VERSION 5.7 ;
  NOWIREEXTENSIONATPIN ON ;
  DIVIDERCHAR "/" ;
  BUSBITCHARS "[]" ;
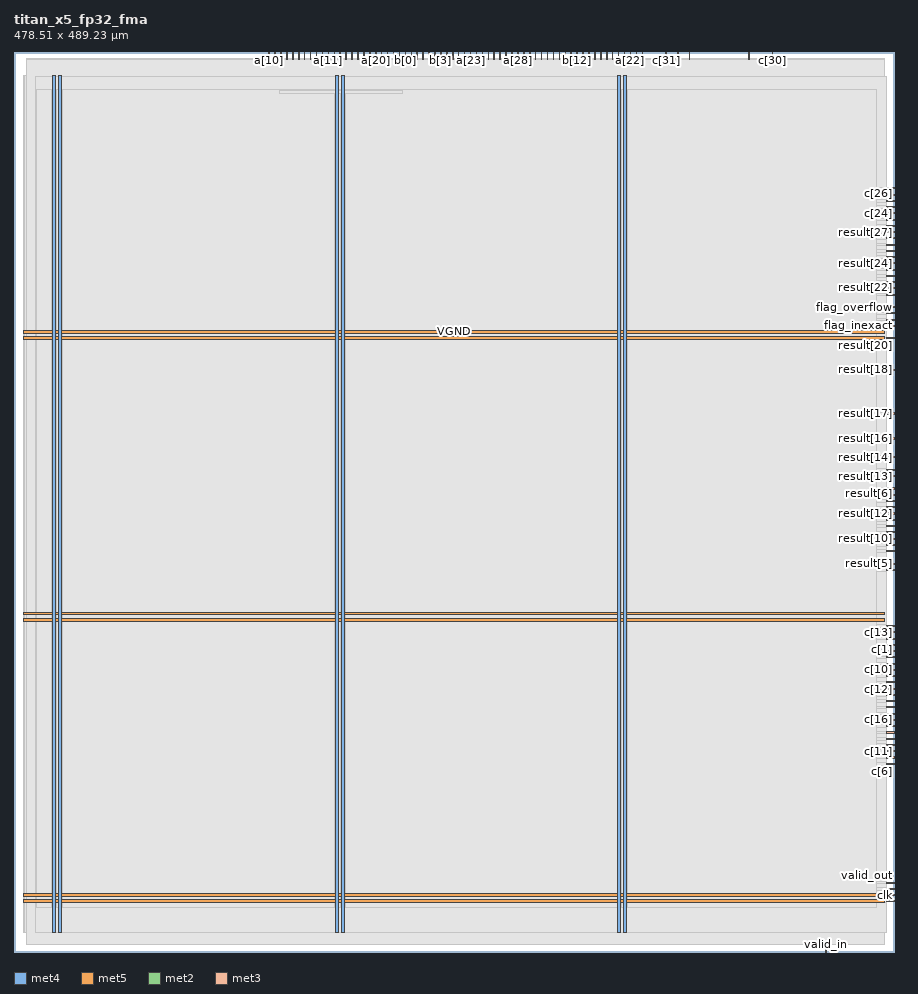
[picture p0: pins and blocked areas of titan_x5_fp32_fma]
MACRO titan_x5_fp32_fma
  CLASS BLOCK ;
  FOREIGN titan_x5_fp32_fma ;
  ORIGIN 0.000 0.000 ;
  SIZE 478.510 BY 489.230 ;
  PIN VGND
    DIRECTION INOUT ;
    USE GROUND ;
    PORT
      LAYER met4 ;
        RECT 24.340 10.640 25.940 476.240 ;
    END
    PORT
      LAYER met4 ;
        RECT 177.940 10.640 179.540 476.240 ;
    END
    PORT
      LAYER met4 ;
        RECT 331.540 10.640 333.140 476.240 ;
    END
    PORT
      LAYER met5 ;
        RECT 5.280 30.030 473.120 31.630 ;
    END
    PORT
      LAYER met5 ;
        RECT 5.280 183.210 473.120 184.810 ;
    END
    PORT
      LAYER met5 ;
        RECT 5.280 336.390 473.120 337.990 ;
    END
  END VGND
  PIN VPWR
    DIRECTION INOUT ;
    USE POWER ;
    PORT
      LAYER met4 ;
        RECT 21.040 10.640 22.640 476.240 ;
    END
    PORT
      LAYER met4 ;
        RECT 174.640 10.640 176.240 476.240 ;
    END
    PORT
      LAYER met4 ;
        RECT 328.240 10.640 329.840 476.240 ;
    END
    PORT
      LAYER met5 ;
        RECT 5.280 26.730 473.120 28.330 ;
    END
    PORT
      LAYER met5 ;
        RECT 5.280 179.910 473.120 181.510 ;
    END
    PORT
      LAYER met5 ;
        RECT 5.280 333.090 473.120 334.690 ;
    END
  END VPWR
  PIN a[0]
    DIRECTION INPUT ;
    USE SIGNAL ;
    ANTENNAGATEAREA 0.196500 ;
    PORT
      LAYER met2 ;
        RECT 199.730 485.230 200.010 489.230 ;
    END
  END a[0]
  PIN a[10]
    DIRECTION INPUT ;
    USE SIGNAL ;
    ANTENNAGATEAREA 0.196500 ;
    PORT
      LAYER met2 ;
        RECT 138.550 485.230 138.830 489.230 ;
    END
  END a[10]
  PIN a[11]
    DIRECTION INPUT ;
    USE SIGNAL ;
    ANTENNAGATEAREA 0.196500 ;
    PORT
      LAYER met2 ;
        RECT 170.750 485.230 171.030 489.230 ;
    END
  END a[11]
  PIN a[12]
    DIRECTION INPUT ;
    USE SIGNAL ;
    ANTENNAGATEAREA 0.196500 ;
    PORT
      LAYER met2 ;
        RECT 157.870 485.230 158.150 489.230 ;
    END
  END a[12]
  PIN a[13]
    DIRECTION INPUT ;
    USE SIGNAL ;
    ANTENNAGATEAREA 0.196500 ;
    PORT
      LAYER met2 ;
        RECT 173.970 485.230 174.250 489.230 ;
    END
  END a[13]
  PIN a[14]
    DIRECTION INPUT ;
    USE SIGNAL ;
    ANTENNAGATEAREA 0.196500 ;
    PORT
      LAYER met2 ;
        RECT 177.190 485.230 177.470 489.230 ;
    END
  END a[14]
  PIN a[15]
    DIRECTION INPUT ;
    USE SIGNAL ;
    ANTENNAGATEAREA 0.196500 ;
    PORT
      LAYER met2 ;
        RECT 141.770 485.230 142.050 489.230 ;
    END
  END a[15]
  PIN a[16]
    DIRECTION INPUT ;
    USE SIGNAL ;
    ANTENNAGATEAREA 0.196500 ;
    PORT
      LAYER met2 ;
        RECT 154.650 485.230 154.930 489.230 ;
    END
  END a[16]
  PIN a[17]
    DIRECTION INPUT ;
    USE SIGNAL ;
    ANTENNAGATEAREA 0.196500 ;
    PORT
      LAYER met2 ;
        RECT 164.310 485.230 164.590 489.230 ;
    END
  END a[17]
  PIN a[18]
    DIRECTION INPUT ;
    USE SIGNAL ;
    ANTENNAGATEAREA 0.196500 ;
    PORT
      LAYER met2 ;
        RECT 180.410 485.230 180.690 489.230 ;
    END
  END a[18]
  PIN a[19]
    DIRECTION INPUT ;
    USE SIGNAL ;
    ANTENNAGATEAREA 0.196500 ;
    PORT
      LAYER met2 ;
        RECT 148.210 485.230 148.490 489.230 ;
    END
  END a[19]
  PIN a[1]
    DIRECTION INPUT ;
    USE SIGNAL ;
    ANTENNAGATEAREA 0.126000 ;
    PORT
      LAYER met2 ;
        RECT 206.170 485.230 206.450 489.230 ;
    END
  END a[1]
  PIN a[20]
    DIRECTION INPUT ;
    USE SIGNAL ;
    ANTENNAGATEAREA 0.196500 ;
    PORT
      LAYER met2 ;
        RECT 196.510 485.230 196.790 489.230 ;
    END
  END a[20]
  PIN a[21]
    DIRECTION INPUT ;
    USE SIGNAL ;
    ANTENNAGATEAREA 0.196500 ;
    PORT
      LAYER met2 ;
        RECT 202.950 485.230 203.230 489.230 ;
    END
  END a[21]
  PIN a[22]
    DIRECTION INPUT ;
    USE SIGNAL ;
    ANTENNAGATEAREA 0.213000 ;
    PORT
      LAYER met2 ;
        RECT 334.970 485.230 335.250 489.230 ;
    END
  END a[22]
  PIN a[23]
    DIRECTION INPUT ;
    USE SIGNAL ;
    ANTENNAGATEAREA 0.196500 ;
    PORT
      LAYER met2 ;
        RECT 248.030 485.230 248.310 489.230 ;
    END
  END a[23]
  PIN a[24]
    DIRECTION INPUT ;
    USE SIGNAL ;
    ANTENNAGATEAREA 0.196500 ;
    PORT
      LAYER met2 ;
        RECT 251.250 485.230 251.530 489.230 ;
    END
  END a[24]
  PIN a[25]
    DIRECTION INPUT ;
    USE SIGNAL ;
    ANTENNAGATEAREA 0.196500 ;
    PORT
      LAYER met2 ;
        RECT 209.390 485.230 209.670 489.230 ;
    END
  END a[25]
  PIN a[26]
    DIRECTION INPUT ;
    USE SIGNAL ;
    ANTENNAGATEAREA 0.196500 ;
    PORT
      LAYER met2 ;
        RECT 244.810 485.230 245.090 489.230 ;
    END
  END a[26]
  PIN a[27]
    DIRECTION INPUT ;
    USE SIGNAL ;
    ANTENNAGATEAREA 0.196500 ;
    PORT
      LAYER met2 ;
        RECT 289.890 485.230 290.170 489.230 ;
    END
  END a[27]
  PIN a[28]
    DIRECTION INPUT ;
    USE SIGNAL ;
    ANTENNAGATEAREA 0.196500 ;
    PORT
      LAYER met2 ;
        RECT 273.790 485.230 274.070 489.230 ;
    END
  END a[28]
  PIN a[29]
    DIRECTION INPUT ;
    USE SIGNAL ;
    ANTENNAGATEAREA 0.196500 ;
    PORT
      LAYER met2 ;
        RECT 286.670 485.230 286.950 489.230 ;
    END
  END a[29]
  PIN a[2]
    DIRECTION INPUT ;
    USE SIGNAL ;
    ANTENNAGATEAREA 0.196500 ;
    PORT
      LAYER met2 ;
        RECT 190.070 485.230 190.350 489.230 ;
    END
  END a[2]
  PIN a[30]
    DIRECTION INPUT ;
    USE SIGNAL ;
    ANTENNAGATEAREA 0.196500 ;
    PORT
      LAYER met2 ;
        RECT 277.010 485.230 277.290 489.230 ;
    END
  END a[30]
  PIN a[31]
    DIRECTION INPUT ;
    USE SIGNAL ;
    ANTENNAGATEAREA 0.196500 ;
    PORT
      LAYER met2 ;
        RECT 341.410 485.230 341.690 489.230 ;
    END
  END a[31]
  PIN a[3]
    DIRECTION INPUT ;
    USE SIGNAL ;
    ANTENNAGATEAREA 0.196500 ;
    PORT
      LAYER met2 ;
        RECT 193.290 485.230 193.570 489.230 ;
    END
  END a[3]
  PIN a[4]
    DIRECTION INPUT ;
    USE SIGNAL ;
    ANTENNAGATEAREA 0.196500 ;
    PORT
      LAYER met2 ;
        RECT 167.530 485.230 167.810 489.230 ;
    END
  END a[4]
  PIN a[5]
    DIRECTION INPUT ;
    USE SIGNAL ;
    ANTENNAGATEAREA 0.196500 ;
    PORT
      LAYER met2 ;
        RECT 186.850 485.230 187.130 489.230 ;
    END
  END a[5]
  PIN a[6]
    DIRECTION INPUT ;
    USE SIGNAL ;
    ANTENNAGATEAREA 0.126000 ;
    PORT
      LAYER met2 ;
        RECT 144.990 485.230 145.270 489.230 ;
    END
  END a[6]
  PIN a[7]
    DIRECTION INPUT ;
    USE SIGNAL ;
    ANTENNAGATEAREA 0.126000 ;
    PORT
      LAYER met2 ;
        RECT 183.630 485.230 183.910 489.230 ;
    END
  END a[7]
  PIN a[8]
    DIRECTION INPUT ;
    USE SIGNAL ;
    ANTENNAGATEAREA 0.196500 ;
    PORT
      LAYER met2 ;
        RECT 151.430 485.230 151.710 489.230 ;
    END
  END a[8]
  PIN a[9]
    DIRECTION INPUT ;
    USE SIGNAL ;
    ANTENNAGATEAREA 0.196500 ;
    PORT
      LAYER met2 ;
        RECT 161.090 485.230 161.370 489.230 ;
    END
  END a[9]
  PIN b[0]
    DIRECTION INPUT ;
    USE SIGNAL ;
    ANTENNAGATEAREA 0.126000 ;
    PORT
      LAYER met2 ;
        RECT 212.610 485.230 212.890 489.230 ;
    END
  END b[0]
  PIN b[10]
    DIRECTION INPUT ;
    USE SIGNAL ;
    ANTENNAGATEAREA 0.126000 ;
    PORT
      LAYER met2 ;
        RECT 322.090 485.230 322.370 489.230 ;
    END
  END b[10]
  PIN b[11]
    DIRECTION INPUT ;
    USE SIGNAL ;
    ANTENNAGATEAREA 0.126000 ;
    PORT
      LAYER met2 ;
        RECT 302.770 485.230 303.050 489.230 ;
    END
  END b[11]
  PIN b[12]
    DIRECTION INPUT ;
    USE SIGNAL ;
    ANTENNAGATEAREA 0.126000 ;
    PORT
      LAYER met2 ;
        RECT 305.990 485.230 306.270 489.230 ;
    END
  END b[12]
  PIN b[13]
    DIRECTION INPUT ;
    USE SIGNAL ;
    ANTENNAGATEAREA 0.196500 ;
    PORT
      LAYER met2 ;
        RECT 264.130 485.230 264.410 489.230 ;
    END
  END b[13]
  PIN b[14]
    DIRECTION INPUT ;
    USE SIGNAL ;
    ANTENNAGATEAREA 0.126000 ;
    PORT
      LAYER met2 ;
        RECT 312.430 485.230 312.710 489.230 ;
    END
  END b[14]
  PIN b[15]
    DIRECTION INPUT ;
    USE SIGNAL ;
    ANTENNAGATEAREA 0.196500 ;
    PORT
      LAYER met2 ;
        RECT 260.910 485.230 261.190 489.230 ;
    END
  END b[15]
  PIN b[16]
    DIRECTION INPUT ;
    USE SIGNAL ;
    ANTENNAGATEAREA 0.196500 ;
    PORT
      LAYER met2 ;
        RECT 267.350 485.230 267.630 489.230 ;
    END
  END b[16]
  PIN b[17]
    DIRECTION INPUT ;
    USE SIGNAL ;
    ANTENNAGATEAREA 0.196500 ;
    PORT
      LAYER met2 ;
        RECT 270.570 485.230 270.850 489.230 ;
    END
  END b[17]
  PIN b[18]
    DIRECTION INPUT ;
    USE SIGNAL ;
    ANTENNAGATEAREA 0.196500 ;
    PORT
      LAYER met2 ;
        RECT 257.690 485.230 257.970 489.230 ;
    END
  END b[18]
  PIN b[19]
    DIRECTION INPUT ;
    USE SIGNAL ;
    ANTENNAGATEAREA 0.126000 ;
    PORT
      LAYER met2 ;
        RECT 318.870 485.230 319.150 489.230 ;
    END
  END b[19]
  PIN b[1]
    DIRECTION INPUT ;
    USE SIGNAL ;
    ANTENNAGATEAREA 0.196500 ;
    PORT
      LAYER met2 ;
        RECT 222.270 485.230 222.550 489.230 ;
    END
  END b[1]
  PIN b[20]
    DIRECTION INPUT ;
    USE SIGNAL ;
    ANTENNAGATEAREA 0.196500 ;
    PORT
      LAYER met2 ;
        RECT 331.750 485.230 332.030 489.230 ;
    END
  END b[20]
  PIN b[21]
    DIRECTION INPUT ;
    USE SIGNAL ;
    ANTENNAGATEAREA 0.196500 ;
    PORT
      LAYER met2 ;
        RECT 254.470 485.230 254.750 489.230 ;
    END
  END b[21]
  PIN b[22]
    DIRECTION INPUT ;
    USE SIGNAL ;
    ANTENNAGATEAREA 0.213000 ;
    PORT
      LAYER met2 ;
        RECT 293.110 485.230 293.390 489.230 ;
    END
  END b[22]
  PIN b[23]
    DIRECTION INPUT ;
    USE SIGNAL ;
    ANTENNAGATEAREA 0.196500 ;
    PORT
      LAYER met2 ;
        RECT 328.530 485.230 328.810 489.230 ;
    END
  END b[23]
  PIN b[24]
    DIRECTION INPUT ;
    USE SIGNAL ;
    ANTENNAGATEAREA 0.126000 ;
    PORT
      LAYER met2 ;
        RECT 325.310 485.230 325.590 489.230 ;
    END
  END b[24]
  PIN b[25]
    DIRECTION INPUT ;
    USE SIGNAL ;
    ANTENNAGATEAREA 0.126000 ;
    PORT
      LAYER met2 ;
        RECT 315.650 485.230 315.930 489.230 ;
    END
  END b[25]
  PIN b[26]
    DIRECTION INPUT ;
    USE SIGNAL ;
    ANTENNAGATEAREA 0.196500 ;
    PORT
      LAYER met2 ;
        RECT 309.210 485.230 309.490 489.230 ;
    END
  END b[26]
  PIN b[27]
    DIRECTION INPUT ;
    USE SIGNAL ;
    ANTENNAGATEAREA 0.196500 ;
    PORT
      LAYER met2 ;
        RECT 299.550 485.230 299.830 489.230 ;
    END
  END b[27]
  PIN b[28]
    DIRECTION INPUT ;
    USE SIGNAL ;
    ANTENNAGATEAREA 0.196500 ;
    PORT
      LAYER met2 ;
        RECT 296.330 485.230 296.610 489.230 ;
    END
  END b[28]
  PIN b[29]
    DIRECTION INPUT ;
    USE SIGNAL ;
    ANTENNAGATEAREA 0.196500 ;
    PORT
      LAYER met2 ;
        RECT 280.230 485.230 280.510 489.230 ;
    END
  END b[29]
  PIN b[2]
    DIRECTION INPUT ;
    USE SIGNAL ;
    ANTENNAGATEAREA 0.196500 ;
    PORT
      LAYER met2 ;
        RECT 225.490 485.230 225.770 489.230 ;
    END
  END b[2]
  PIN b[30]
    DIRECTION INPUT ;
    USE SIGNAL ;
    ANTENNAGATEAREA 0.196500 ;
    PORT
      LAYER met2 ;
        RECT 283.450 485.230 283.730 489.230 ;
    END
  END b[30]
  PIN b[31]
    DIRECTION INPUT ;
    USE SIGNAL ;
    ANTENNAGATEAREA 0.196500 ;
    PORT
      LAYER met2 ;
        RECT 338.190 485.230 338.470 489.230 ;
    END
  END b[31]
  PIN b[3]
    DIRECTION INPUT ;
    USE SIGNAL ;
    ANTENNAGATEAREA 0.196500 ;
    PORT
      LAYER met2 ;
        RECT 231.930 485.230 232.210 489.230 ;
    END
  END b[3]
  PIN b[4]
    DIRECTION INPUT ;
    USE SIGNAL ;
    ANTENNAGATEAREA 0.196500 ;
    PORT
      LAYER met2 ;
        RECT 215.830 485.230 216.110 489.230 ;
    END
  END b[4]
  PIN b[5]
    DIRECTION INPUT ;
    USE SIGNAL ;
    ANTENNAGATEAREA 0.196500 ;
    PORT
      LAYER met2 ;
        RECT 219.050 485.230 219.330 489.230 ;
    END
  END b[5]
  PIN b[6]
    DIRECTION INPUT ;
    USE SIGNAL ;
    ANTENNAGATEAREA 0.196500 ;
    PORT
      LAYER met2 ;
        RECT 228.710 485.230 228.990 489.230 ;
    END
  END b[6]
  PIN b[7]
    DIRECTION INPUT ;
    USE SIGNAL ;
    ANTENNAGATEAREA 0.196500 ;
    PORT
      LAYER met2 ;
        RECT 235.150 485.230 235.430 489.230 ;
    END
  END b[7]
  PIN b[8]
    DIRECTION INPUT ;
    USE SIGNAL ;
    ANTENNAGATEAREA 0.196500 ;
    PORT
      LAYER met2 ;
        RECT 238.370 485.230 238.650 489.230 ;
    END
  END b[8]
  PIN b[9]
    DIRECTION INPUT ;
    USE SIGNAL ;
    ANTENNAGATEAREA 0.196500 ;
    PORT
      LAYER met2 ;
        RECT 241.590 485.230 241.870 489.230 ;
    END
  END b[9]
  PIN c[0]
    DIRECTION INPUT ;
    USE SIGNAL ;
    ANTENNAGATEAREA 0.159000 ;
    PORT
      LAYER met3 ;
        RECT 474.510 132.640 478.510 133.240 ;
    END
  END c[0]
  PIN c[10]
    DIRECTION INPUT ;
    USE SIGNAL ;
    ANTENNAGATEAREA 0.213000 ;
    PORT
      LAYER met3 ;
        RECT 474.510 153.040 478.510 153.640 ;
    END
  END c[10]
  PIN c[11]
    DIRECTION INPUT ;
    USE SIGNAL ;
    ANTENNAGATEAREA 0.213000 ;
    PORT
      LAYER met3 ;
        RECT 474.510 108.840 478.510 109.440 ;
    END
  END c[11]
  PIN c[12]
    DIRECTION INPUT ;
    USE SIGNAL ;
    ANTENNAGATEAREA 0.213000 ;
    PORT
      LAYER met3 ;
        RECT 474.510 146.240 478.510 146.840 ;
    END
  END c[12]
  PIN c[13]
    DIRECTION INPUT ;
    USE SIGNAL ;
    ANTENNAGATEAREA 0.159000 ;
    PORT
      LAYER met3 ;
        RECT 474.510 173.440 478.510 174.040 ;
    END
  END c[13]
  PIN c[14]
    DIRECTION INPUT ;
    USE SIGNAL ;
    ANTENNAGATEAREA 0.159000 ;
    PORT
      LAYER met3 ;
        RECT 474.510 166.640 478.510 167.240 ;
    END
  END c[14]
  PIN c[15]
    DIRECTION INPUT ;
    USE SIGNAL ;
    ANTENNAGATEAREA 0.213000 ;
    PORT
      LAYER met3 ;
        RECT 474.510 112.240 478.510 112.840 ;
    END
  END c[15]
  PIN c[16]
    DIRECTION INPUT ;
    USE SIGNAL ;
    ANTENNAGATEAREA 0.213000 ;
    PORT
      LAYER met3 ;
        RECT 474.510 125.840 478.510 126.440 ;
    END
  END c[16]
  PIN c[17]
    DIRECTION INPUT ;
    USE SIGNAL ;
    ANTENNAGATEAREA 0.213000 ;
    PORT
      LAYER met3 ;
        RECT 474.510 115.640 478.510 116.240 ;
    END
  END c[17]
  PIN c[18]
    DIRECTION INPUT ;
    USE SIGNAL ;
    ANTENNAGATEAREA 0.126000 ;
    PORT
      LAYER met3 ;
        RECT 474.510 119.040 478.510 119.640 ;
    END
  END c[18]
  PIN c[19]
    DIRECTION INPUT ;
    USE SIGNAL ;
    ANTENNAGATEAREA 0.126000 ;
    PORT
      LAYER met3 ;
        RECT 474.510 122.440 478.510 123.040 ;
    END
  END c[19]
  PIN c[1]
    DIRECTION INPUT ;
    USE SIGNAL ;
    ANTENNAGATEAREA 0.159000 ;
    PORT
      LAYER met3 ;
        RECT 474.510 159.840 478.510 160.440 ;
    END
  END c[1]
  PIN c[20]
    DIRECTION INPUT ;
    USE SIGNAL ;
    ANTENNAGATEAREA 0.196500 ;
    PORT
      LAYER met3 ;
        RECT 474.510 136.040 478.510 136.640 ;
    END
  END c[20]
  PIN c[21]
    DIRECTION INPUT ;
    USE SIGNAL ;
    ANTENNAGATEAREA 0.159000 ;
    PORT
      LAYER met3 ;
        RECT 474.510 176.840 478.510 177.440 ;
    END
  END c[21]
  PIN c[22]
    DIRECTION INPUT ;
    USE SIGNAL ;
    ANTENNAGATEAREA 0.213000 ;
    PORT
      LAYER met3 ;
        RECT 474.510 163.240 478.510 163.840 ;
    END
  END c[22]
  PIN c[23]
    DIRECTION INPUT ;
    USE SIGNAL ;
    ANTENNAGATEAREA 0.126000 ;
    PORT
      LAYER met3 ;
        RECT 474.510 394.440 478.510 395.040 ;
    END
  END c[23]
  PIN c[24]
    DIRECTION INPUT ;
    USE SIGNAL ;
    ANTENNAGATEAREA 0.196500 ;
    PORT
      LAYER met3 ;
        RECT 474.510 401.240 478.510 401.840 ;
    END
  END c[24]
  PIN c[25]
    DIRECTION INPUT ;
    USE SIGNAL ;
    ANTENNAGATEAREA 0.196500 ;
    PORT
      LAYER met3 ;
        RECT 474.510 397.840 478.510 398.440 ;
    END
  END c[25]
  PIN c[26]
    DIRECTION INPUT ;
    USE SIGNAL ;
    ANTENNAGATEAREA 0.159000 ;
    PORT
      LAYER met3 ;
        RECT 474.510 408.040 478.510 408.640 ;
    END
  END c[26]
  PIN c[27]
    DIRECTION INPUT ;
    USE SIGNAL ;
    ANTENNAGATEAREA 0.213000 ;
    PORT
      LAYER met3 ;
        RECT 474.510 404.640 478.510 405.240 ;
    END
  END c[27]
  PIN c[28]
    DIRECTION INPUT ;
    USE SIGNAL ;
    ANTENNAGATEAREA 0.196500 ;
    PORT
      LAYER met3 ;
        RECT 474.510 411.440 478.510 412.040 ;
    END
  END c[28]
  PIN c[29]
    DIRECTION INPUT ;
    USE SIGNAL ;
    ANTENNAGATEAREA 0.126000 ;
    PORT
      LAYER met3 ;
        RECT 474.510 414.840 478.510 415.440 ;
    END
  END c[29]
  PIN c[2]
    DIRECTION INPUT ;
    USE SIGNAL ;
    ANTENNAGATEAREA 0.159000 ;
    PORT
      LAYER met3 ;
        RECT 474.510 139.440 478.510 140.040 ;
    END
  END c[2]
  PIN c[30]
    DIRECTION INPUT ;
    USE SIGNAL ;
    ANTENNAGATEAREA 0.213000 ;
    PORT
      LAYER met2 ;
        RECT 412.250 485.230 412.530 489.230 ;
    END
  END c[30]
  PIN c[31]
    DIRECTION INPUT ;
    USE SIGNAL ;
    ANTENNAGATEAREA 0.196500 ;
    PORT
      LAYER met2 ;
        RECT 354.290 485.230 354.570 489.230 ;
    END
  END c[31]
  PIN c[3]
    DIRECTION INPUT ;
    USE SIGNAL ;
    ANTENNAGATEAREA 0.213000 ;
    PORT
      LAYER met3 ;
        RECT 474.510 129.240 478.510 129.840 ;
    END
  END c[3]
  PIN c[4]
    DIRECTION INPUT ;
    USE SIGNAL ;
    ANTENNAGATEAREA 0.213000 ;
    PORT
      LAYER met3 ;
        RECT 474.510 149.640 478.510 150.240 ;
    END
  END c[4]
  PIN c[5]
    DIRECTION INPUT ;
    USE SIGNAL ;
    ANTENNAGATEAREA 0.196500 ;
    PORT
      LAYER met3 ;
        RECT 474.510 105.440 478.510 106.040 ;
    END
  END c[5]
  PIN c[6]
    DIRECTION INPUT ;
    USE SIGNAL ;
    ANTENNAGATEAREA 0.196500 ;
    PORT
      LAYER met3 ;
        RECT 474.510 102.040 478.510 102.640 ;
    END
  END c[6]
  PIN c[7]
    DIRECTION INPUT ;
    USE SIGNAL ;
    ANTENNAGATEAREA 0.213000 ;
    PORT
      LAYER met3 ;
        RECT 474.510 170.040 478.510 170.640 ;
    END
  END c[7]
  PIN c[8]
    DIRECTION INPUT ;
    USE SIGNAL ;
    ANTENNAGATEAREA 0.213000 ;
    PORT
      LAYER met3 ;
        RECT 474.510 142.840 478.510 143.440 ;
    END
  END c[8]
  PIN c[9]
    DIRECTION INPUT ;
    USE SIGNAL ;
    ANTENNAGATEAREA 0.213000 ;
    PORT
      LAYER met3 ;
        RECT 474.510 156.440 478.510 157.040 ;
    END
  END c[9]
  PIN clk
    DIRECTION INPUT ;
    USE SIGNAL ;
    ANTENNAGATEAREA 0.852000 ;
    PORT
      LAYER met3 ;
        RECT 474.510 30.640 478.510 31.240 ;
    END
  END clk
  PIN en
    DIRECTION INPUT ;
    USE SIGNAL ;
    ANTENNAGATEAREA 0.213000 ;
    PORT
      LAYER met3 ;
        RECT 474.510 27.240 478.510 27.840 ;
    END
  END en
  PIN flag_inexact
    DIRECTION OUTPUT ;
    USE SIGNAL ;
    ANTENNADIFFAREA 0.445500 ;
    PORT
      LAYER met3 ;
        RECT 474.510 340.040 478.510 340.640 ;
    END
  END flag_inexact
  PIN flag_invalid
    DIRECTION OUTPUT ;
    USE SIGNAL ;
    ANTENNADIFFAREA 0.445500 ;
    PORT
      LAYER met2 ;
        RECT 399.370 485.230 399.650 489.230 ;
    END
  END flag_invalid
  PIN flag_overflow
    DIRECTION OUTPUT ;
    USE SIGNAL ;
    ANTENNADIFFAREA 0.445500 ;
    PORT
      LAYER met3 ;
        RECT 474.510 350.240 478.510 350.840 ;
    END
  END flag_overflow
  PIN flag_underflow
    DIRECTION OUTPUT ;
    USE SIGNAL ;
    ANTENNADIFFAREA 0.445500 ;
    PORT
      LAYER met3 ;
        RECT 474.510 343.440 478.510 344.040 ;
    END
  END flag_underflow
  PIN result[0]
    DIRECTION OUTPUT ;
    USE SIGNAL ;
    ANTENNADIFFAREA 0.445500 ;
    PORT
      LAYER met3 ;
        RECT 474.510 234.640 478.510 235.240 ;
    END
  END result[0]
  PIN result[10]
    DIRECTION OUTPUT ;
    USE SIGNAL ;
    ANTENNADIFFAREA 0.445500 ;
    PORT
      LAYER met3 ;
        RECT 474.510 224.440 478.510 225.040 ;
    END
  END result[10]
  PIN result[11]
    DIRECTION OUTPUT ;
    USE SIGNAL ;
    ANTENNADIFFAREA 0.445500 ;
    PORT
      LAYER met3 ;
        RECT 474.510 251.640 478.510 252.240 ;
    END
  END result[11]
  PIN result[12]
    DIRECTION OUTPUT ;
    USE SIGNAL ;
    ANTENNADIFFAREA 0.445500 ;
    PORT
      LAYER met3 ;
        RECT 474.510 238.040 478.510 238.640 ;
    END
  END result[12]
  PIN result[13]
    DIRECTION OUTPUT ;
    USE SIGNAL ;
    ANTENNADIFFAREA 0.445500 ;
    PORT
      LAYER met3 ;
        RECT 474.510 258.440 478.510 259.040 ;
    END
  END result[13]
  PIN result[14]
    DIRECTION OUTPUT ;
    USE SIGNAL ;
    ANTENNADIFFAREA 0.445500 ;
    PORT
      LAYER met3 ;
        RECT 474.510 268.640 478.510 269.240 ;
    END
  END result[14]
  PIN result[15]
    DIRECTION OUTPUT ;
    USE SIGNAL ;
    ANTENNADIFFAREA 0.445500 ;
    PORT
      LAYER met3 ;
        RECT 474.510 261.840 478.510 262.440 ;
    END
  END result[15]
  PIN result[16]
    DIRECTION OUTPUT ;
    USE SIGNAL ;
    ANTENNADIFFAREA 0.445500 ;
    PORT
      LAYER met3 ;
        RECT 474.510 278.840 478.510 279.440 ;
    END
  END result[16]
  PIN result[17]
    DIRECTION OUTPUT ;
    USE SIGNAL ;
    ANTENNADIFFAREA 0.445500 ;
    PORT
      LAYER met3 ;
        RECT 474.510 292.440 478.510 293.040 ;
    END
  END result[17]
  PIN result[18]
    DIRECTION OUTPUT ;
    USE SIGNAL ;
    ANTENNADIFFAREA 0.445500 ;
    PORT
      LAYER met3 ;
        RECT 474.510 316.240 478.510 316.840 ;
    END
  END result[18]
  PIN result[19]
    DIRECTION OUTPUT ;
    USE SIGNAL ;
    ANTENNADIFFAREA 0.445500 ;
    PORT
      LAYER met3 ;
        RECT 474.510 346.840 478.510 347.440 ;
    END
  END result[19]
  PIN result[1]
    DIRECTION OUTPUT ;
    USE SIGNAL ;
    ANTENNADIFFAREA 0.445500 ;
    PORT
      LAYER met3 ;
        RECT 474.510 217.640 478.510 218.240 ;
    END
  END result[1]
  PIN result[20]
    DIRECTION OUTPUT ;
    USE SIGNAL ;
    ANTENNADIFFAREA 0.445500 ;
    PORT
      LAYER met3 ;
        RECT 474.510 333.240 478.510 333.840 ;
    END
  END result[20]
  PIN result[21]
    DIRECTION OUTPUT ;
    USE SIGNAL ;
    ANTENNADIFFAREA 0.445500 ;
    PORT
      LAYER met3 ;
        RECT 474.510 360.440 478.510 361.040 ;
    END
  END result[21]
  PIN result[22]
    DIRECTION OUTPUT ;
    USE SIGNAL ;
    ANTENNADIFFAREA 0.445500 ;
    PORT
      LAYER met3 ;
        RECT 474.510 357.040 478.510 357.640 ;
    END
  END result[22]
  PIN result[23]
    DIRECTION OUTPUT ;
    USE SIGNAL ;
    ANTENNADIFFAREA 0.445500 ;
    PORT
      LAYER met3 ;
        RECT 474.510 363.840 478.510 364.440 ;
    END
  END result[23]
  PIN result[24]
    DIRECTION OUTPUT ;
    USE SIGNAL ;
    ANTENNADIFFAREA 0.445500 ;
    PORT
      LAYER met3 ;
        RECT 474.510 374.040 478.510 374.640 ;
    END
  END result[24]
  PIN result[25]
    DIRECTION OUTPUT ;
    USE SIGNAL ;
    ANTENNADIFFAREA 0.445500 ;
    PORT
      LAYER met3 ;
        RECT 474.510 367.240 478.510 367.840 ;
    END
  END result[25]
  PIN result[26]
    DIRECTION OUTPUT ;
    USE SIGNAL ;
    ANTENNADIFFAREA 0.445500 ;
    PORT
      LAYER met3 ;
        RECT 474.510 370.640 478.510 371.240 ;
    END
  END result[26]
  PIN result[27]
    DIRECTION OUTPUT ;
    USE SIGNAL ;
    ANTENNADIFFAREA 0.445500 ;
    PORT
      LAYER met3 ;
        RECT 474.510 391.040 478.510 391.640 ;
    END
  END result[27]
  PIN result[28]
    DIRECTION OUTPUT ;
    USE SIGNAL ;
    ANTENNADIFFAREA 0.445500 ;
    PORT
      LAYER met3 ;
        RECT 474.510 384.240 478.510 384.840 ;
    END
  END result[28]
  PIN result[29]
    DIRECTION OUTPUT ;
    USE SIGNAL ;
    ANTENNADIFFAREA 0.445500 ;
    PORT
      LAYER met3 ;
        RECT 474.510 387.640 478.510 388.240 ;
    END
  END result[29]
  PIN result[2]
    DIRECTION OUTPUT ;
    USE SIGNAL ;
    ANTENNADIFFAREA 0.445500 ;
    PORT
      LAYER met3 ;
        RECT 474.510 221.040 478.510 221.640 ;
    END
  END result[2]
  PIN result[30]
    DIRECTION OUTPUT ;
    USE SIGNAL ;
    ANTENNADIFFAREA 0.445500 ;
    PORT
      LAYER met3 ;
        RECT 474.510 380.840 478.510 381.440 ;
    END
  END result[30]
  PIN result[31]
    DIRECTION OUTPUT ;
    USE SIGNAL ;
    ANTENNADIFFAREA 0.445500 ;
    PORT
      LAYER met3 ;
        RECT 474.510 377.440 478.510 378.040 ;
    END
  END result[31]
  PIN result[3]
    DIRECTION OUTPUT ;
    USE SIGNAL ;
    ANTENNADIFFAREA 0.445500 ;
    PORT
      LAYER met3 ;
        RECT 474.510 227.840 478.510 228.440 ;
    END
  END result[3]
  PIN result[4]
    DIRECTION OUTPUT ;
    USE SIGNAL ;
    ANTENNADIFFAREA 0.445500 ;
    PORT
      LAYER met3 ;
        RECT 474.510 231.240 478.510 231.840 ;
    END
  END result[4]
  PIN result[5]
    DIRECTION OUTPUT ;
    USE SIGNAL ;
    ANTENNADIFFAREA 0.445500 ;
    PORT
      LAYER met3 ;
        RECT 474.510 210.840 478.510 211.440 ;
    END
  END result[5]
  PIN result[6]
    DIRECTION OUTPUT ;
    USE SIGNAL ;
    ANTENNADIFFAREA 0.445500 ;
    PORT
      LAYER met3 ;
        RECT 474.510 244.840 478.510 245.440 ;
    END
  END result[6]
  PIN result[7]
    DIRECTION OUTPUT ;
    USE SIGNAL ;
    ANTENNADIFFAREA 0.445500 ;
    PORT
      LAYER met3 ;
        RECT 474.510 241.440 478.510 242.040 ;
    END
  END result[7]
  PIN result[8]
    DIRECTION OUTPUT ;
    USE SIGNAL ;
    ANTENNADIFFAREA 0.445500 ;
    PORT
      LAYER met3 ;
        RECT 474.510 248.240 478.510 248.840 ;
    END
  END result[8]
  PIN result[9]
    DIRECTION OUTPUT ;
    USE SIGNAL ;
    ANTENNADIFFAREA 0.445500 ;
    PORT
      LAYER met3 ;
        RECT 474.510 207.440 478.510 208.040 ;
    END
  END result[9]
  PIN rm[0]
    DIRECTION INPUT ;
    USE SIGNAL ;
    ANTENNAGATEAREA 0.196500 ;
    PORT
      LAYER met2 ;
        RECT 360.730 485.230 361.010 489.230 ;
    END
  END rm[0]
  PIN rm[1]
    DIRECTION INPUT ;
    USE SIGNAL ;
    ANTENNAGATEAREA 0.196500 ;
    PORT
      LAYER met2 ;
        RECT 367.170 485.230 367.450 489.230 ;
    END
  END rm[1]
  PIN rst_n
    DIRECTION INPUT ;
    USE SIGNAL ;
    ANTENNAGATEAREA 0.196500 ;
    PORT
      LAYER met3 ;
        RECT 474.510 34.040 478.510 34.640 ;
    END
  END rst_n
  PIN valid_in
    DIRECTION INPUT ;
    USE SIGNAL ;
    ANTENNAGATEAREA 0.196500 ;
    PORT
      LAYER met2 ;
        RECT 441.230 0.000 441.510 4.000 ;
    END
  END valid_in
  PIN valid_out
    DIRECTION OUTPUT ;
    USE SIGNAL ;
    ANTENNADIFFAREA 0.445500 ;
    PORT
      LAYER met3 ;
        RECT 474.510 37.440 478.510 38.040 ;
    END
  END valid_out
  OBS
      LAYER nwell ;
        RECT 5.330 10.795 473.070 476.190 ;
      LAYER li1 ;
        RECT 5.520 10.795 472.880 476.085 ;
      LAYER met1 ;
        RECT 5.520 10.640 473.270 476.240 ;
      LAYER met2 ;
        RECT 6.540 484.950 138.270 485.930 ;
        RECT 139.110 484.950 141.490 485.930 ;
        RECT 142.330 484.950 144.710 485.930 ;
        RECT 145.550 484.950 147.930 485.930 ;
        RECT 148.770 484.950 151.150 485.930 ;
        RECT 151.990 484.950 154.370 485.930 ;
        RECT 155.210 484.950 157.590 485.930 ;
        RECT 158.430 484.950 160.810 485.930 ;
        RECT 161.650 484.950 164.030 485.930 ;
        RECT 164.870 484.950 167.250 485.930 ;
        RECT 168.090 484.950 170.470 485.930 ;
        RECT 171.310 484.950 173.690 485.930 ;
        RECT 174.530 484.950 176.910 485.930 ;
        RECT 177.750 484.950 180.130 485.930 ;
        RECT 180.970 484.950 183.350 485.930 ;
        RECT 184.190 484.950 186.570 485.930 ;
        RECT 187.410 484.950 189.790 485.930 ;
        RECT 190.630 484.950 193.010 485.930 ;
        RECT 193.850 484.950 196.230 485.930 ;
        RECT 197.070 484.950 199.450 485.930 ;
        RECT 200.290 484.950 202.670 485.930 ;
        RECT 203.510 484.950 205.890 485.930 ;
        RECT 206.730 484.950 209.110 485.930 ;
        RECT 209.950 484.950 212.330 485.930 ;
        RECT 213.170 484.950 215.550 485.930 ;
        RECT 216.390 484.950 218.770 485.930 ;
        RECT 219.610 484.950 221.990 485.930 ;
        RECT 222.830 484.950 225.210 485.930 ;
        RECT 226.050 484.950 228.430 485.930 ;
        RECT 229.270 484.950 231.650 485.930 ;
        RECT 232.490 484.950 234.870 485.930 ;
        RECT 235.710 484.950 238.090 485.930 ;
        RECT 238.930 484.950 241.310 485.930 ;
        RECT 242.150 484.950 244.530 485.930 ;
        RECT 245.370 484.950 247.750 485.930 ;
        RECT 248.590 484.950 250.970 485.930 ;
        RECT 251.810 484.950 254.190 485.930 ;
        RECT 255.030 484.950 257.410 485.930 ;
        RECT 258.250 484.950 260.630 485.930 ;
        RECT 261.470 484.950 263.850 485.930 ;
        RECT 264.690 484.950 267.070 485.930 ;
        RECT 267.910 484.950 270.290 485.930 ;
        RECT 271.130 484.950 273.510 485.930 ;
        RECT 274.350 484.950 276.730 485.930 ;
        RECT 277.570 484.950 279.950 485.930 ;
        RECT 280.790 484.950 283.170 485.930 ;
        RECT 284.010 484.950 286.390 485.930 ;
        RECT 287.230 484.950 289.610 485.930 ;
        RECT 290.450 484.950 292.830 485.930 ;
        RECT 293.670 484.950 296.050 485.930 ;
        RECT 296.890 484.950 299.270 485.930 ;
        RECT 300.110 484.950 302.490 485.930 ;
        RECT 303.330 484.950 305.710 485.930 ;
        RECT 306.550 484.950 308.930 485.930 ;
        RECT 309.770 484.950 312.150 485.930 ;
        RECT 312.990 484.950 315.370 485.930 ;
        RECT 316.210 484.950 318.590 485.930 ;
        RECT 319.430 484.950 321.810 485.930 ;
        RECT 322.650 484.950 325.030 485.930 ;
        RECT 325.870 484.950 328.250 485.930 ;
        RECT 329.090 484.950 331.470 485.930 ;
        RECT 332.310 484.950 334.690 485.930 ;
        RECT 335.530 484.950 337.910 485.930 ;
        RECT 338.750 484.950 341.130 485.930 ;
        RECT 341.970 484.950 354.010 485.930 ;
        RECT 354.850 484.950 360.450 485.930 ;
        RECT 361.290 484.950 366.890 485.930 ;
        RECT 367.730 484.950 399.090 485.930 ;
        RECT 399.930 484.950 411.970 485.930 ;
        RECT 412.810 484.950 473.240 485.930 ;
        RECT 6.540 4.280 473.240 484.950 ;
        RECT 6.540 4.000 440.950 4.280 ;
        RECT 441.790 4.000 473.240 4.280 ;
      LAYER met3 ;
        RECT 11.800 415.840 474.510 476.165 ;
        RECT 11.800 414.440 474.110 415.840 ;
        RECT 11.800 412.440 474.510 414.440 ;
        RECT 11.800 411.040 474.110 412.440 ;
        RECT 11.800 409.040 474.510 411.040 ;
        RECT 11.800 407.640 474.110 409.040 ;
        RECT 11.800 405.640 474.510 407.640 ;
        RECT 11.800 404.240 474.110 405.640 ;
        RECT 11.800 402.240 474.510 404.240 ;
        RECT 11.800 400.840 474.110 402.240 ;
        RECT 11.800 398.840 474.510 400.840 ;
        RECT 11.800 397.440 474.110 398.840 ;
        RECT 11.800 395.440 474.510 397.440 ;
        RECT 11.800 394.040 474.110 395.440 ;
        RECT 11.800 392.040 474.510 394.040 ;
        RECT 11.800 390.640 474.110 392.040 ;
        RECT 11.800 388.640 474.510 390.640 ;
        RECT 11.800 387.240 474.110 388.640 ;
        RECT 11.800 385.240 474.510 387.240 ;
        RECT 11.800 383.840 474.110 385.240 ;
        RECT 11.800 381.840 474.510 383.840 ;
        RECT 11.800 380.440 474.110 381.840 ;
        RECT 11.800 378.440 474.510 380.440 ;
        RECT 11.800 377.040 474.110 378.440 ;
        RECT 11.800 375.040 474.510 377.040 ;
        RECT 11.800 373.640 474.110 375.040 ;
        RECT 11.800 371.640 474.510 373.640 ;
        RECT 11.800 370.240 474.110 371.640 ;
        RECT 11.800 368.240 474.510 370.240 ;
        RECT 11.800 366.840 474.110 368.240 ;
        RECT 11.800 364.840 474.510 366.840 ;
        RECT 11.800 363.440 474.110 364.840 ;
        RECT 11.800 361.440 474.510 363.440 ;
        RECT 11.800 360.040 474.110 361.440 ;
        RECT 11.800 358.040 474.510 360.040 ;
        RECT 11.800 356.640 474.110 358.040 ;
        RECT 11.800 351.240 474.510 356.640 ;
        RECT 11.800 349.840 474.110 351.240 ;
        RECT 11.800 347.840 474.510 349.840 ;
        RECT 11.800 346.440 474.110 347.840 ;
        RECT 11.800 344.440 474.510 346.440 ;
        RECT 11.800 343.040 474.110 344.440 ;
        RECT 11.800 341.040 474.510 343.040 ;
        RECT 11.800 339.640 474.110 341.040 ;
        RECT 11.800 334.240 474.510 339.640 ;
        RECT 11.800 332.840 474.110 334.240 ;
        RECT 11.800 317.240 474.510 332.840 ;
        RECT 11.800 315.840 474.110 317.240 ;
        RECT 11.800 293.440 474.510 315.840 ;
        RECT 11.800 292.040 474.110 293.440 ;
        RECT 11.800 279.840 474.510 292.040 ;
        RECT 11.800 278.440 474.110 279.840 ;
        RECT 11.800 269.640 474.510 278.440 ;
        RECT 11.800 268.240 474.110 269.640 ;
        RECT 11.800 262.840 474.510 268.240 ;
        RECT 11.800 261.440 474.110 262.840 ;
        RECT 11.800 259.440 474.510 261.440 ;
        RECT 11.800 258.040 474.110 259.440 ;
        RECT 11.800 252.640 474.510 258.040 ;
        RECT 11.800 251.240 474.110 252.640 ;
        RECT 11.800 249.240 474.510 251.240 ;
        RECT 11.800 247.840 474.110 249.240 ;
        RECT 11.800 245.840 474.510 247.840 ;
        RECT 11.800 244.440 474.110 245.840 ;
        RECT 11.800 242.440 474.510 244.440 ;
        RECT 11.800 241.040 474.110 242.440 ;
        RECT 11.800 239.040 474.510 241.040 ;
        RECT 11.800 237.640 474.110 239.040 ;
        RECT 11.800 235.640 474.510 237.640 ;
        RECT 11.800 234.240 474.110 235.640 ;
        RECT 11.800 232.240 474.510 234.240 ;
        RECT 11.800 230.840 474.110 232.240 ;
        RECT 11.800 228.840 474.510 230.840 ;
        RECT 11.800 227.440 474.110 228.840 ;
        RECT 11.800 225.440 474.510 227.440 ;
        RECT 11.800 224.040 474.110 225.440 ;
        RECT 11.800 222.040 474.510 224.040 ;
        RECT 11.800 220.640 474.110 222.040 ;
        RECT 11.800 218.640 474.510 220.640 ;
        RECT 11.800 217.240 474.110 218.640 ;
        RECT 11.800 211.840 474.510 217.240 ;
        RECT 11.800 210.440 474.110 211.840 ;
        RECT 11.800 208.440 474.510 210.440 ;
        RECT 11.800 207.040 474.110 208.440 ;
        RECT 11.800 177.840 474.510 207.040 ;
        RECT 11.800 176.440 474.110 177.840 ;
        RECT 11.800 174.440 474.510 176.440 ;
        RECT 11.800 173.040 474.110 174.440 ;
        RECT 11.800 171.040 474.510 173.040 ;
        RECT 11.800 169.640 474.110 171.040 ;
        RECT 11.800 167.640 474.510 169.640 ;
        RECT 11.800 166.240 474.110 167.640 ;
        RECT 11.800 164.240 474.510 166.240 ;
        RECT 11.800 162.840 474.110 164.240 ;
        RECT 11.800 160.840 474.510 162.840 ;
        RECT 11.800 159.440 474.110 160.840 ;
        RECT 11.800 157.440 474.510 159.440 ;
        RECT 11.800 156.040 474.110 157.440 ;
        RECT 11.800 154.040 474.510 156.040 ;
        RECT 11.800 152.640 474.110 154.040 ;
        RECT 11.800 150.640 474.510 152.640 ;
        RECT 11.800 149.240 474.110 150.640 ;
        RECT 11.800 147.240 474.510 149.240 ;
        RECT 11.800 145.840 474.110 147.240 ;
        RECT 11.800 143.840 474.510 145.840 ;
        RECT 11.800 142.440 474.110 143.840 ;
        RECT 11.800 140.440 474.510 142.440 ;
        RECT 11.800 139.040 474.110 140.440 ;
        RECT 11.800 137.040 474.510 139.040 ;
        RECT 11.800 135.640 474.110 137.040 ;
        RECT 11.800 133.640 474.510 135.640 ;
        RECT 11.800 132.240 474.110 133.640 ;
        RECT 11.800 130.240 474.510 132.240 ;
        RECT 11.800 128.840 474.110 130.240 ;
        RECT 11.800 126.840 474.510 128.840 ;
        RECT 11.800 125.440 474.110 126.840 ;
        RECT 11.800 123.440 474.510 125.440 ;
        RECT 11.800 122.040 474.110 123.440 ;
        RECT 11.800 120.040 474.510 122.040 ;
        RECT 11.800 118.640 474.110 120.040 ;
        RECT 11.800 116.640 474.510 118.640 ;
        RECT 11.800 115.240 474.110 116.640 ;
        RECT 11.800 113.240 474.510 115.240 ;
        RECT 11.800 111.840 474.110 113.240 ;
        RECT 11.800 109.840 474.510 111.840 ;
        RECT 11.800 108.440 474.110 109.840 ;
        RECT 11.800 106.440 474.510 108.440 ;
        RECT 11.800 105.040 474.110 106.440 ;
        RECT 11.800 103.040 474.510 105.040 ;
        RECT 11.800 101.640 474.110 103.040 ;
        RECT 11.800 38.440 474.510 101.640 ;
        RECT 11.800 37.040 474.110 38.440 ;
        RECT 11.800 35.040 474.510 37.040 ;
        RECT 11.800 33.640 474.110 35.040 ;
        RECT 11.800 31.640 474.510 33.640 ;
        RECT 11.800 30.240 474.110 31.640 ;
        RECT 11.800 28.240 474.510 30.240 ;
        RECT 11.800 26.840 474.110 28.240 ;
        RECT 11.800 10.715 474.510 26.840 ;
      LAYER met4 ;
        RECT 12.255 23.975 20.640 469.025 ;
        RECT 23.040 23.975 23.940 469.025 ;
        RECT 26.340 23.975 174.240 469.025 ;
        RECT 176.640 23.975 177.540 469.025 ;
        RECT 179.940 23.975 327.840 469.025 ;
        RECT 330.240 23.975 331.140 469.025 ;
        RECT 333.540 23.975 468.905 469.025 ;
      LAYER met5 ;
        RECT 144.100 466.700 211.020 468.300 ;
  END
END titan_x5_fp32_fma
END LIBRARY

